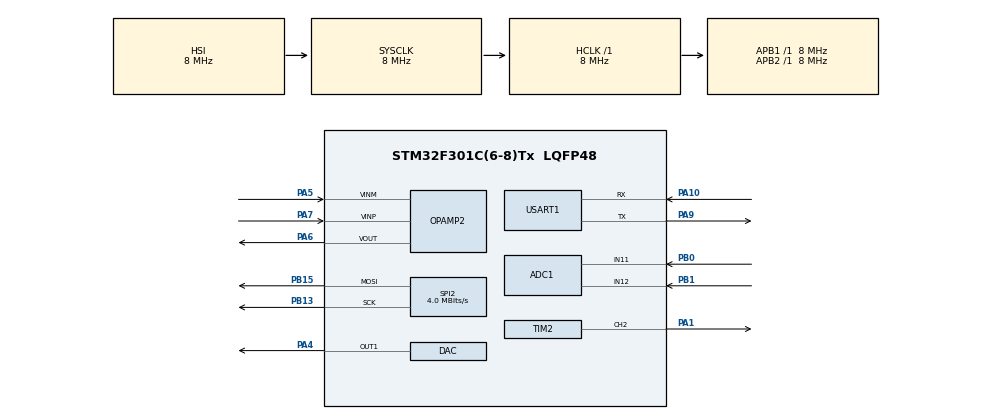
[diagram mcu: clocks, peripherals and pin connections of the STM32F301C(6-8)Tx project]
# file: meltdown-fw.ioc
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ADC1.Channel-0\#ChannelRegularConversion=ADC_CHANNEL_11
ADC1.NbrOfConversionFlag=1
ADC1.Offset-0\#ChannelRegularConversion=0
ADC1.OffsetNumber-0\#ChannelRegularConversion=ADC_OFFSET_NONE
ADC1.Rank-0\#ChannelRegularConversion=1
ADC1.SamplingTime-0\#ChannelRegularConversion=ADC_SAMPLETIME_1CYCLE_5
ADC1.master=1
Mcu.Family=STM32F3
Mcu.Name=STM32F301C(6-8)Tx
Mcu.Package=LQFP48
NVIC.PriorityGroup=NVIC_PRIORITYGROUP_4
PA1.Signal=S_TIM2_CH2
PA10.Mode=Asynchronous
PA10.Signal=USART1_RX
PA4.Signal=COMP_DAC1_group
PA5.Mode=PGA Connected
PA5.Signal=OPAMP2_VINM
PA6.Mode=PGA Connected
PA6.Signal=OPAMP2_VOUT
PA7.Mode=PGA Connected
PA7.Signal=OPAMP2_VINP
PA9.Mode=Asynchronous
PA9.Signal=USART1_TX
PB0.Mode=IN11-Single-Ended
PB0.Signal=ADC1_IN11
PB1.Mode=IN12-Single-Ended
PB1.Signal=ADC1_IN12
PB13.Mode=TX_Only_Simplex_Unidirect_Master
PB13.Signal=SPI2_SCK
PB15.Mode=TX_Only_Simplex_Unidirect_Master
PB15.Signal=SPI2_MOSI
PF0-OSC_IN.Mode=HSE-External-Oscillator
PF0-OSC_IN.Signal=RCC_OSC_IN
PF1-OSC_OUT.Mode=HSE-External-Oscillator
PF1-OSC_OUT.Signal=RCC_OSC_OUT
ProjectManager.HeapSize=0x200
ProjectManager.StackSize=0x400
ProjectManager.TargetToolchain=STM32CubeIDE
RCC.AHBFreq_Value=8000000
RCC.APB1Freq_Value=8000000
RCC.APB2Freq_Value=8000000
RCC.CortexFreq_Value=8000000
RCC.HSE_VALUE=8000000
RCC.HSI_VALUE=8000000
RCC.LSE_VALUE=32768
RCC.PLLMUL=RCC_PLL_MUL4
RCC.SYSCLKFreq_VALUE=8000000
SH.COMP_DAC1_group.0=DAC_OUT1,DAC_OUT1
SH.S_TIM2_CH2.0=TIM2_CH2,PWM Generation2 CH2
SPI2.CalculateBaudRate=4.0 MBits/s
SPI2.Direction=SPI_DIRECTION_2LINES
SPI2.Mode=SPI_MODE_MASTER
SPI2.VirtualType=VM_MASTER
TIM2.Channel-PWM\ Generation2\ CH2=TIM_CHANNEL_2
USART1.VirtualMode-Asynchronous=VM_ASYNC
board=custom

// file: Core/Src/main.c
/* USER CODE BEGIN Header */
/**
  ******************************************************************************
  * @file           : main.c
  * @brief          : Main program body
  ******************************************************************************
  * @attention
  *
  * Copyright (c) 2022 STMicroelectronics.
  * All rights reserved.
  *
  * This software is licensed under terms that can be found in the LICENSE file
  * in the root directory of this software component.
  * If no LICENSE file comes with this software, it is provided AS-IS.
  *
  ******************************************************************************
  */
/* USER CODE END Header */
#include "main.h"

ADC_HandleTypeDef hadc1;

DAC_HandleTypeDef hdac;

OPAMP_HandleTypeDef hopamp2;

SPI_HandleTypeDef hspi2;

TIM_HandleTypeDef htim2;

UART_HandleTypeDef huart1;

void SystemClock_Config(void);
static void MX_GPIO_Init(void);
static void MX_ADC1_Init(void);
static void MX_DAC_Init(void);
static void MX_OPAMP2_Init(void);
static void MX_SPI2_Init(void);
static void MX_TIM2_Init(void);
static void MX_USART1_UART_Init(void);

int main(void)
{

  /* MCU Configuration--------------------------------------------------------*/

  /* Reset of all peripherals, Initializes the Flash interface and the Systick. */
  HAL_Init();

  /* Configure the system clock */
  SystemClock_Config();

  /* Initialize all configured peripherals */
  MX_GPIO_Init();
  MX_ADC1_Init();
  MX_DAC_Init();
  MX_OPAMP2_Init();
  MX_SPI2_Init();
  MX_TIM2_Init();
  MX_USART1_UART_Init();

  /* Infinite loop */
  while (1)
  {

  }
}

void SystemClock_Config(void)
{
  RCC_OscInitTypeDef RCC_OscInitStruct = {0};
  RCC_ClkInitTypeDef RCC_ClkInitStruct = {0};
  RCC_PeriphCLKInitTypeDef PeriphClkInit = {0};

  /** Initializes the RCC Oscillators according to the specified parameters
  * in the RCC_OscInitTypeDef structure.
  */
  RCC_OscInitStruct.OscillatorType = RCC_OSCILLATORTYPE_HSI;
  RCC_OscInitStruct.HSIState = RCC_HSI_ON;
  RCC_OscInitStruct.HSICalibrationValue = RCC_HSICALIBRATION_DEFAULT;
  RCC_OscInitStruct.PLL.PLLState = RCC_PLL_ON;
  RCC_OscInitStruct.PLL.PLLSource = RCC_PLLSOURCE_HSI;
  RCC_OscInitStruct.PLL.PLLMUL = RCC_PLL_MUL4;
  if (HAL_RCC_OscConfig(&RCC_OscInitStruct) != HAL_OK)
  {
    Error_Handler();
  }

  /** Initializes the CPU, AHB and APB buses clocks
  */
  RCC_ClkInitStruct.ClockType = RCC_CLOCKTYPE_HCLK|RCC_CLOCKTYPE_SYSCLK
                              |RCC_CLOCKTYPE_PCLK1|RCC_CLOCKTYPE_PCLK2;
  RCC_ClkInitStruct.SYSCLKSource = RCC_SYSCLKSOURCE_HSI;
  RCC_ClkInitStruct.AHBCLKDivider = RCC_SYSCLK_DIV1;
  RCC_ClkInitStruct.APB1CLKDivider = RCC_HCLK_DIV1;
  RCC_ClkInitStruct.APB2CLKDivider = RCC_HCLK_DIV1;

  if (HAL_RCC_ClockConfig(&RCC_ClkInitStruct, FLASH_LATENCY_0) != HAL_OK)
  {
    Error_Handler();
  }
  PeriphClkInit.PeriphClockSelection = RCC_PERIPHCLK_USART1|RCC_PERIPHCLK_ADC1;
  PeriphClkInit.Usart1ClockSelection = RCC_USART1CLKSOURCE_PCLK1;
  PeriphClkInit.Adc1ClockSelection = RCC_ADC1PLLCLK_DIV1;

  if (HAL_RCCEx_PeriphCLKConfig(&PeriphClkInit) != HAL_OK)
  {
    Error_Handler();
  }
}

static void MX_ADC1_Init(void)
{

  ADC_ChannelConfTypeDef sConfig = {0};

  /** Common config
  */
  hadc1.Instance = ADC1;
  hadc1.Init.ClockPrescaler = ADC_CLOCK_ASYNC_DIV1;
  hadc1.Init.Resolution = ADC_RESOLUTION_12B;
  hadc1.Init.ScanConvMode = ADC_SCAN_DISABLE;
  hadc1.Init.ContinuousConvMode = DISABLE;
  hadc1.Init.DiscontinuousConvMode = DISABLE;
  hadc1.Init.ExternalTrigConvEdge = ADC_EXTERNALTRIGCONVEDGE_NONE;
  hadc1.Init.ExternalTrigConv = ADC_SOFTWARE_START;
  hadc1.Init.DataAlign = ADC_DATAALIGN_RIGHT;
  hadc1.Init.NbrOfConversion = 1;
  hadc1.Init.DMAContinuousRequests = DISABLE;
  hadc1.Init.EOCSelection = ADC_EOC_SINGLE_CONV;
  hadc1.Init.LowPowerAutoWait = DISABLE;
  hadc1.Init.Overrun = ADC_OVR_DATA_OVERWRITTEN;
  if (HAL_ADC_Init(&hadc1) != HAL_OK)
  {
    Error_Handler();
  }

  /** Configure Regular Channel
  */
  sConfig.Channel = ADC_CHANNEL_11;
  sConfig.Rank = ADC_REGULAR_RANK_1;
  sConfig.SingleDiff = ADC_SINGLE_ENDED;
  sConfig.SamplingTime = ADC_SAMPLETIME_1CYCLE_5;
  sConfig.OffsetNumber = ADC_OFFSET_NONE;
  sConfig.Offset = 0;
  if (HAL_ADC_ConfigChannel(&hadc1, &sConfig) != HAL_OK)
  {
    Error_Handler();
  }

}

static void MX_DAC_Init(void)
{

  DAC_ChannelConfTypeDef sConfig = {0};

  /** DAC Initialization
  */
  hdac.Instance = DAC;
  if (HAL_DAC_Init(&hdac) != HAL_OK)
  {
    Error_Handler();
  }

  /** DAC channel OUT1 config
  */
  sConfig.DAC_Trigger = DAC_TRIGGER_NONE;
  sConfig.DAC_OutputBuffer = DAC_OUTPUTBUFFER_ENABLE;
  if (HAL_DAC_ConfigChannel(&hdac, &sConfig, DAC_CHANNEL_1) != HAL_OK)
  {
    Error_Handler();
  }

}

static void MX_OPAMP2_Init(void)
{

  hopamp2.Instance = OPAMP2;
  hopamp2.Init.Mode = OPAMP_PGA_MODE;
  hopamp2.Init.NonInvertingInput = OPAMP_NONINVERTINGINPUT_IO0;
  hopamp2.Init.TimerControlledMuxmode = OPAMP_TIMERCONTROLLEDMUXMODE_DISABLE;
  hopamp2.Init.PgaConnect = OPAMP_PGA_CONNECT_INVERTINGINPUT_IO1;
  hopamp2.Init.PgaGain = OPAMP_PGA_GAIN_2;
  hopamp2.Init.UserTrimming = OPAMP_TRIMMING_FACTORY;
  if (HAL_OPAMP_Init(&hopamp2) != HAL_OK)
  {
    Error_Handler();
  }

}

static void MX_SPI2_Init(void)
{

  /* SPI2 parameter configuration*/
  hspi2.Instance = SPI2;
  hspi2.Init.Mode = SPI_MODE_MASTER;
  hspi2.Init.Direction = SPI_DIRECTION_2LINES;
  hspi2.Init.DataSize = SPI_DATASIZE_4BIT;
  hspi2.Init.CLKPolarity = SPI_POLARITY_LOW;
  hspi2.Init.CLKPhase = SPI_PHASE_1EDGE;
  hspi2.Init.NSS = SPI_NSS_SOFT;
  hspi2.Init.BaudRatePrescaler = SPI_BAUDRATEPRESCALER_2;
  hspi2.Init.FirstBit = SPI_FIRSTBIT_MSB;
  hspi2.Init.TIMode = SPI_TIMODE_DISABLE;
  hspi2.Init.CRCCalculation = SPI_CRCCALCULATION_DISABLE;
  hspi2.Init.CRCPolynomial = 7;
  hspi2.Init.CRCLength = SPI_CRC_LENGTH_DATASIZE;
  hspi2.Init.NSSPMode = SPI_NSS_PULSE_ENABLE;
  if (HAL_SPI_Init(&hspi2) != HAL_OK)
  {
    Error_Handler();
  }

}

static void MX_TIM2_Init(void)
{

  TIM_MasterConfigTypeDef sMasterConfig = {0};
  TIM_OC_InitTypeDef sConfigOC = {0};

  htim2.Instance = TIM2;
  htim2.Init.Prescaler = 0;
  htim2.Init.CounterMode = TIM_COUNTERMODE_UP;
  htim2.Init.Period = 4294967295;
  htim2.Init.ClockDivision = TIM_CLOCKDIVISION_DIV1;
  htim2.Init.AutoReloadPreload = TIM_AUTORELOAD_PRELOAD_DISABLE;
  if (HAL_TIM_PWM_Init(&htim2) != HAL_OK)
  {
    Error_Handler();
  }
  sMasterConfig.MasterOutputTrigger = TIM_TRGO_RESET;
  sMasterConfig.MasterSlaveMode = TIM_MASTERSLAVEMODE_DISABLE;
  if (HAL_TIMEx_MasterConfigSynchronization(&htim2, &sMasterConfig) != HAL_OK)
  {
    Error_Handler();
  }
  sConfigOC.OCMode = TIM_OCMODE_PWM1;
  sConfigOC.Pulse = 0;
  sConfigOC.OCPolarity = TIM_OCPOLARITY_HIGH;
  sConfigOC.OCFastMode = TIM_OCFAST_DISABLE;
  if (HAL_TIM_PWM_ConfigChannel(&htim2, &sConfigOC, TIM_CHANNEL_2) != HAL_OK)
  {
    Error_Handler();
  }
  HAL_TIM_MspPostInit(&htim2);

}

static void MX_USART1_UART_Init(void)
{

  huart1.Instance = USART1;
  huart1.Init.BaudRate = 38400;
  huart1.Init.WordLength = UART_WORDLENGTH_8B;
  huart1.Init.StopBits = UART_STOPBITS_1;
  huart1.Init.Parity = UART_PARITY_NONE;
  huart1.Init.Mode = UART_MODE_TX_RX;
  huart1.Init.HwFlowCtl = UART_HWCONTROL_NONE;
  huart1.Init.OverSampling = UART_OVERSAMPLING_16;
  huart1.Init.OneBitSampling = UART_ONE_BIT_SAMPLE_DISABLE;
  huart1.AdvancedInit.AdvFeatureInit = UART_ADVFEATURE_NO_INIT;
  if (HAL_UART_Init(&huart1) != HAL_OK)
  {
    Error_Handler();
  }

}

static void MX_GPIO_Init(void)
{
  GPIO_InitTypeDef GPIO_InitStruct = {0};

  /* GPIO Ports Clock Enable */
  __HAL_RCC_GPIOF_CLK_ENABLE();
  __HAL_RCC_GPIOA_CLK_ENABLE();
  __HAL_RCC_GPIOB_CLK_ENABLE();

  /*Configure GPIO pin : Protection_INT_Pin */
  GPIO_InitStruct.Pin = Protection_INT_Pin;
  GPIO_InitStruct.Mode = GPIO_MODE_IT_RISING;
  GPIO_InitStruct.Pull = GPIO_NOPULL;
  HAL_GPIO_Init(Protection_INT_GPIO_Port, &GPIO_InitStruct);

  /*Configure GPIO pins : ENC_BTN_INT_Pin ENC_B_INT_Pin */
  GPIO_InitStruct.Pin = ENC_BTN_INT_Pin|ENC_B_INT_Pin;
  GPIO_InitStruct.Mode = GPIO_MODE_IT_RISING;
  GPIO_InitStruct.Pull = GPIO_NOPULL;
  HAL_GPIO_Init(GPIOA, &GPIO_InitStruct);

}

void Error_Handler(void)
{
  __disable_irq();
  while (1)
  {
  }
}
